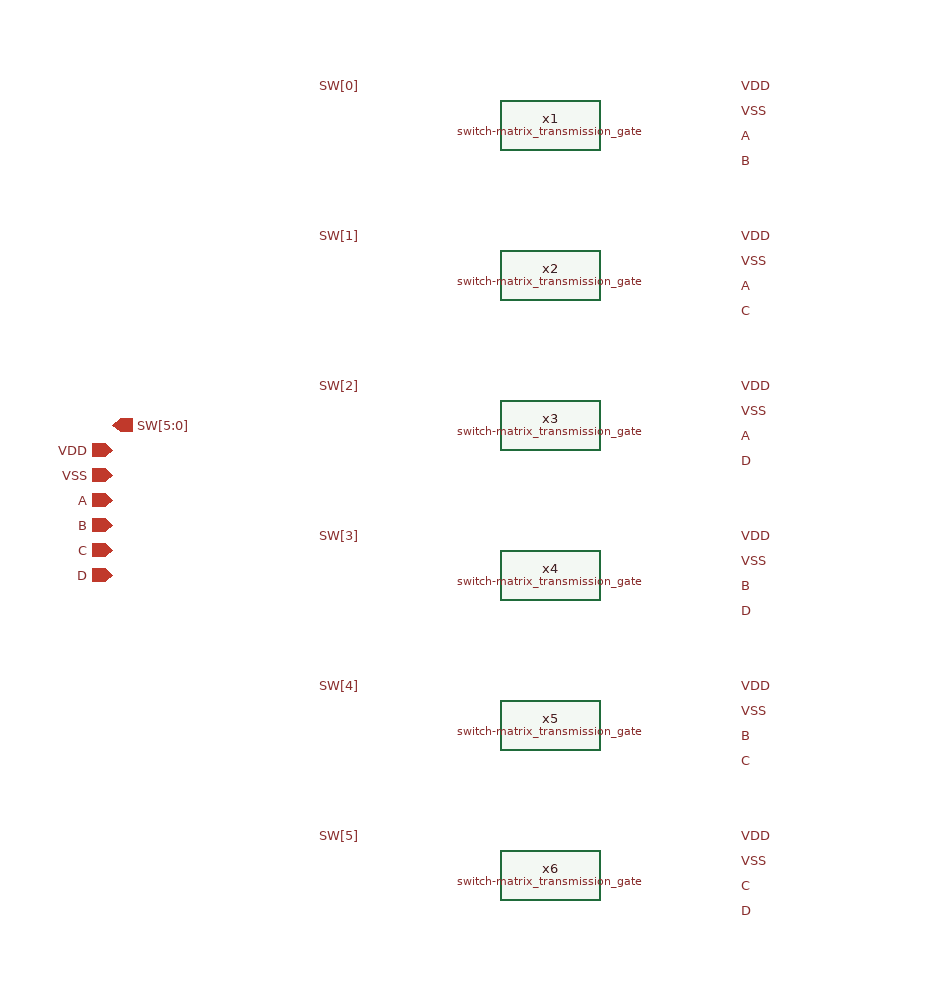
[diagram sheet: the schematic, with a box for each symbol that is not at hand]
v {xschem version=3.4.7 file_version=1.2}
G {}
K {}
V {}
S {}
E {}
C {/foss/designs/sscs-chipathon2025-LNA/designs/libs/core_analog/switch-matrix/switch-matrix_transmission_gate.sym} 390 -740 0 0 {name=x1}
C {/foss/designs/sscs-chipathon2025-LNA/designs/libs/core_analog/switch-matrix/switch-matrix_transmission_gate.sym} 390 -620 0 0 {name=x2}
C {/foss/designs/sscs-chipathon2025-LNA/designs/libs/core_analog/switch-matrix/switch-matrix_transmission_gate.sym} 390 -500 0 0 {name=x3}
C {/foss/designs/sscs-chipathon2025-LNA/designs/libs/core_analog/switch-matrix/switch-matrix_transmission_gate.sym} 390 -380 0 0 {name=x4}
C {/foss/designs/sscs-chipathon2025-LNA/designs/libs/core_analog/switch-matrix/switch-matrix_transmission_gate.sym} 390 -260 0 0 {name=x5}
C {/foss/designs/sscs-chipathon2025-LNA/designs/libs/core_analog/switch-matrix/switch-matrix_transmission_gate.sym} 390 -140 0 0 {name=x6}
C {lab_wire.sym} 540 -770 0 1 {name=p1 lab=VDD}
C {lab_wire.sym} 540 -750 0 1 {name=p2 lab=VSS}
C {lab_wire.sym} 240 -770 0 0 {name=p3 lab=SW[0]}
C {lab_wire.sym} 540 -730 0 1 {name=p4 lab=A}
C {lab_wire.sym} 540 -710 0 1 {name=p5 lab=B}
C {lab_wire.sym} 540 -650 0 1 {name=p6 lab=VDD}
C {lab_wire.sym} 540 -630 0 1 {name=p7 lab=VSS}
C {lab_wire.sym} 240 -650 0 0 {name=p8 lab=SW[1]}
C {lab_wire.sym} 540 -610 0 1 {name=p9 lab=A}
C {lab_wire.sym} 540 -590 0 1 {name=p10 lab=C}
C {lab_wire.sym} 540 -530 0 1 {name=p11 lab=VDD}
C {lab_wire.sym} 540 -510 0 1 {name=p12 lab=VSS}
C {lab_wire.sym} 240 -530 0 0 {name=p13 lab=SW[2]}
C {lab_wire.sym} 540 -490 0 1 {name=p14 lab=A}
C {lab_wire.sym} 540 -470 0 1 {name=p15 lab=D}
C {lab_wire.sym} 540 -410 0 1 {name=p16 lab=VDD}
C {lab_wire.sym} 540 -390 0 1 {name=p17 lab=VSS}
C {lab_wire.sym} 240 -410 0 0 {name=p18 lab=SW[3]}
C {lab_wire.sym} 540 -370 0 1 {name=p19 lab=B}
C {lab_wire.sym} 540 -350 0 1 {name=p20 lab=D}
C {lab_wire.sym} 540 -290 0 1 {name=p21 lab=VDD}
C {lab_wire.sym} 540 -270 0 1 {name=p22 lab=VSS}
C {lab_wire.sym} 240 -290 0 0 {name=p23 lab=SW[4]}
C {lab_wire.sym} 540 -250 0 1 {name=p24 lab=B}
C {lab_wire.sym} 540 -230 0 1 {name=p25 lab=C}
C {lab_wire.sym} 540 -170 0 1 {name=p26 lab=VDD}
C {lab_wire.sym} 540 -150 0 1 {name=p27 lab=VSS}
C {lab_wire.sym} 240 -170 0 0 {name=p28 lab=SW[5]}
C {lab_wire.sym} 540 -130 0 1 {name=p29 lab=C}
C {lab_wire.sym} 540 -110 0 1 {name=p30 lab=D}
C {iopin.sym} 40 -480 0 0 {name=p31 lab=VDD}
C {iopin.sym} 40 -460 0 0 {name=p32 lab=VSS}
C {ipin.sym} 40 -500 0 1 {name=p33 lab=SW[5:0]}
C {iopin.sym} 40 -440 0 0 {name=p34 lab=A}
C {iopin.sym} 40 -420 0 0 {name=p35 lab=B}
C {iopin.sym} 40 -400 0 0 {name=p36 lab=C}
C {iopin.sym} 40 -380 0 0 {name=p37 lab=D}
